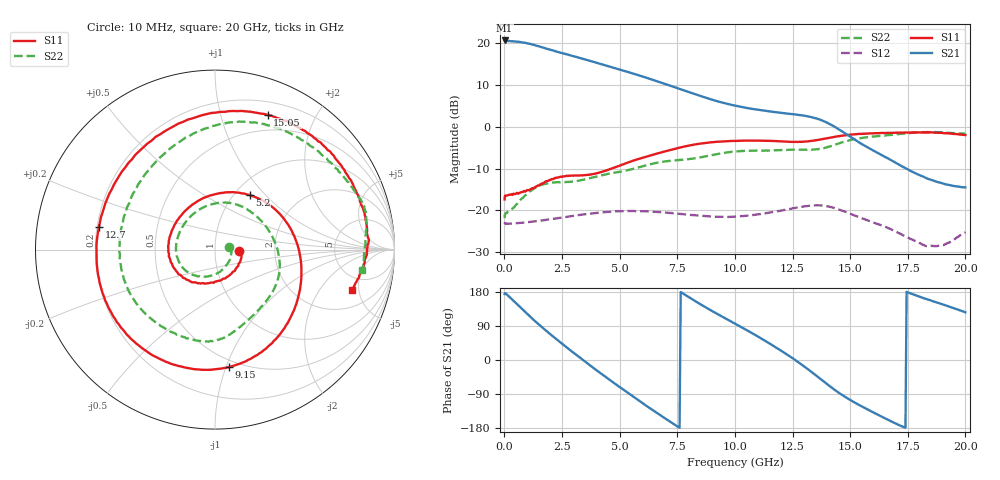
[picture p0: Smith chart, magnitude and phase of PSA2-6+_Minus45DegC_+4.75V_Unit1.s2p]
!Keysight Technologies,N5242A,MY47200155,A.10.49.08
!Date: Thursday, October 19, 2023 15:27:46
!Correction: S11(Full 2 Port(1,2))
!S21(Full 2 Port(1,2))
!S12(Full 2 Port(1,2))
!S22(Full 2 Port(1,2))
!S2P File: Measurements: S11, S21, S12, S22:
# Hz S  dB  R 50
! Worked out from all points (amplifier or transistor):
!   408 points, 10 MHz to 20 GHz, reference 50 ohm
!   highest |S21| = 20.6 dB at 10 MHz (marker M1)
!   |S21| within 3 dB of that: start of sweep to 2.502 GHz
!   unconditionally stable (mu >= 1): start of sweep to 1.139 GHz; 3.702 GHz to end of sweep
!   at 3.05 GHz: K = 0.98, MSG = 19.0 dB, |S12| = -21.2 dB
!   at 9.85 GHz: K = 1.20, MAG = 10.7 dB, |S12| = -21.5 dB
!   at 20 GHz: K = 5.15, MAG = -4.7 dB, |S12| = -25.2 dB
!   S11 on the Smith chart (normalised r, x): 10 MHz: 1.31, -0.02; 5.2 GHz: 1.17, +0.82; 9.15 GHz: 0.44, -1.03; 12.7 GHz: 0.21, +0.09; 15.05 GHz: 0.33, +1.41; 20 GHz: 3.40, -4.21
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1e7  -17.38 -3.2  20.62 174.3  -23.22 -4.9  -21.83 8.4
7e7  -16.49 -6.6  20.49 175.0  -23.17 -1.8  -20.61 -10.0
4e8  -15.99 -35.4  20.38 155.8  -23.10 -6.8  -19.34 -54.9
8e8  -15.58 -66.5  20.14 132.4  -22.93 -13.7  -17.00 -94.1
1.1e9  -15.07 -86.9  19.82 115.2  -22.75 -19.3  -15.43 -116.2
1.4e9  -14.24 -104.2  19.37 98.7  -22.54 -25.1  -14.40 -134.2
1.9e9  -12.92 -130.9  18.55 72.7  -22.16 -35.1  -13.50 -160.0
2.4e9  -12.00 -156.2  17.75 48.0  -21.76 -46.1  -13.27 175.4
2.85e9  -11.72 -179.6  17.09 26.1  -21.39 -56.8  -13.17 151.4
3.35e9  -11.63 153.9  16.32 2.4  -21.00 -69.2  -12.74 124.5
4.3e9  -10.64 103.3  14.80 -40.6  -20.43 -94.3  -11.47 79.0
5.2e9  -8.87 57.5  13.35 -80.0  -20.15 -119.6  -10.57 39.0
6e9  -7.39 20.5  12.00 -114.2  -20.17 -142.0  -9.46 6.6
6.7e9  -6.29 -8.7  10.73 -143.1  -20.39 -161.1  -8.51 -15.9
8e9  -4.51 -52.7  8.29 165.8  -21.03 165.7  -7.75 -51.4
9.15e9  -3.62 -83.1  6.24 124.5  -21.52 140.1  -6.62 -76.4
1.005e10  -3.37 -104.8  4.99 94.4  -21.44 122.1  -5.90 -90.2
1.27e10  -3.62 168.9  2.87 -3.5  -19.31 55.9  -5.47 -160.3
1.335e10  -3.38 137.4  2.25 -32.7  -18.84 33.0  -5.50 170.6
1.505e10  -1.87 68.6  -2.54 -107.2  -20.89 -28.7  -3.14 88.5
1.67e10  -1.47 32.6  -7.74 -159.5  -24.31 -71.8  -1.99 42.0
2e10  -1.98 -16.6  -14.49 125.8  -25.19 -102.5  -1.65 -7.8
